VERSION 5.7 ;
  NOWIREEXTENSIONATPIN ON ;
  DIVIDERCHAR "/" ;
  BUSBITCHARS "[]" ;
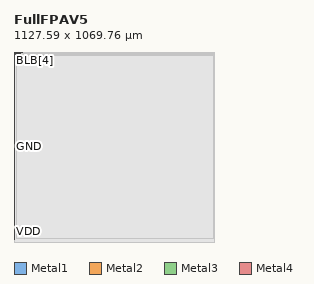
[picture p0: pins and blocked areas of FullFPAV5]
MACRO FullFPAV5
  CLASS BLOCK ;
  FOREIGN FullFPAV5 ;
  ORIGIN 4.030 43.635 ;
  SIZE 1127.585 BY 1069.755 ;
  PIN GND
    ANTENNADIFFAREA 23708.671875 ;
    PORT
      LAYER Metal1 ;
        RECT -1.255 -27.215 -0.265 1013.280 ;
    END
  END GND
  PIN VDD
    USE POWER ;
    PORT
      LAYER Metal2 ;
        RECT -1.260 -27.210 -0.270 1013.300 ;
    END
  END VDD
  PIN SF
    ANTENNAGATEAREA 1024.000000 ;
    PORT
      LAYER Metal3 ;
        RECT -3.460 1001.620 -2.905 1026.085 ;
    END
  END SF
  PIN SET
    ANTENNAGATEAREA 602.112000 ;
    PORT
      LAYER Metal3 ;
        RECT -0.725 1004.865 -0.360 1026.030 ;
    END
  END SET
  PIN IREF
    PORT
      LAYER Metal3 ;
        RECT -0.055 1010.730 0.285 1025.980 ;
    END
  END IREF
  PIN Ramp
    ANTENNADIFFAREA 559.923157 ;
    PORT
      LAYER Metal3 ;
        RECT 0.795 1011.685 1.135 1025.965 ;
    END
  END Ramp
  PIN VINP
    ANTENNADIFFAREA 1119.846313 ;
    PORT
      LAYER Metal3 ;
        RECT 29.815 1008.505 30.215 1025.625 ;
    END
  END VINP
  PIN phase
    ANTENNAGATEAREA 1324.646362 ;
    PORT
      LAYER Metal3 ;
        RECT 32.240 1003.345 32.580 1025.510 ;
    END
  END phase
  PIN RST
    ANTENNAGATEAREA 1024.000000 ;
    PORT
      LAYER Metal3 ;
        RECT 33.330 1012.435 33.670 1025.515 ;
    END
  END RST
  PIN BL[1]
    ANTENNADIFFAREA 270.950378 ;
    PORT
      LAYER Metal4 ;
        RECT 2.050 1025.745 36.770 1026.120 ;
    END
  END BL[1]
  PIN BL[0]
    ANTENNADIFFAREA 270.950378 ;
    PORT
      LAYER Metal4 ;
        RECT 1.390 1025.135 2.610 1025.455 ;
    END
  END BL[0]
  PIN BLB[1]
    ANTENNADIFFAREA 270.950378 ;
    PORT
      LAYER Metal4 ;
        RECT 3.640 1024.525 38.360 1024.845 ;
    END
  END BLB[1]
  PIN BLB[0]
    ANTENNADIFFAREA 270.950378 ;
    PORT
      LAYER Metal4 ;
        RECT 7.225 1023.785 41.945 1024.075 ;
    END
  END BLB[0]
  PIN BLB[2]
    ANTENNADIFFAREA 270.950378 ;
    PORT
      LAYER Metal4 ;
        RECT 9.315 1023.145 44.035 1023.465 ;
    END
  END BLB[2]
  PIN BLB[3]
    ANTENNADIFFAREA 270.950378 ;
    PORT
      LAYER Metal4 ;
        RECT 1.570 1022.455 12.615 1022.775 ;
    END
  END BLB[3]
  PIN BL[2]
    ANTENNADIFFAREA 270.950378 ;
    PORT
      LAYER Metal4 ;
        RECT 1.510 1021.745 13.560 1022.065 ;
    END
  END BL[2]
  PIN BLB[7]
    ANTENNADIFFAREA 270.950378 ;
    PORT
      LAYER Metal4 ;
        RECT 1.450 1017.480 25.065 1017.800 ;
    END
  END BLB[7]
  PIN BL[4]
    ANTENNADIFFAREA 270.950378 ;
    PORT
      LAYER Metal3 ;
        RECT 15.590 1019.040 15.870 1019.320 ;
      LAYER Metal4 ;
        RECT 15.590 1019.040 15.870 1019.320 ;
    END
  END BL[4]
  PIN BLB[6]
    ANTENNADIFFAREA 270.950378 ;
    PORT
      LAYER Metal3 ;
        RECT 25.725 1016.505 26.005 1016.785 ;
      LAYER Metal4 ;
        RECT 25.725 1016.505 26.005 1016.785 ;
    END
  END BLB[6]
  PIN BL[6]
    ANTENNADIFFAREA 270.950378 ;
    PORT
      LAYER Metal3 ;
        RECT 26.680 1015.420 26.960 1015.700 ;
      LAYER Metal4 ;
        RECT 26.680 1015.420 26.960 1015.700 ;
    END
  END BL[6]
  PIN BL[7]
    ANTENNADIFFAREA 270.950378 ;
    PORT
      LAYER Metal3 ;
        RECT 27.325 1014.650 27.605 1014.930 ;
      LAYER Metal4 ;
        RECT 27.325 1014.650 27.605 1014.930 ;
    END
  END BL[7]
  PIN BLB[5]
    ANTENNADIFFAREA 270.950378 ;
    PORT
      LAYER Metal4 ;
        RECT 1.440 1013.960 28.280 1014.280 ;
    END
  END BLB[5]
  PIN BLB[4]
    ANTENNADIFFAREA 270.950378 ;
    PORT
      LAYER Metal3 ;
        RECT 29.120 1013.330 29.400 1013.610 ;
      LAYER Metal4 ;
        RECT 29.120 1013.330 29.400 1013.610 ;
    END
  END BLB[4]
  PIN BL[3]
    ANTENNADIFFAREA 270.950378 ;
    PORT
      LAYER Metal3 ;
        RECT 14.190 1020.835 14.470 1021.115 ;
      LAYER Metal4 ;
        RECT 14.190 1020.835 14.470 1021.115 ;
    END
  END BL[3]
  PIN BL[5]
    ANTENNADIFFAREA 270.950378 ;
    PORT
      LAYER Metal3 ;
        RECT 14.950 1020.050 15.230 1020.330 ;
      LAYER Metal4 ;
        RECT 14.950 1020.050 15.230 1020.330 ;
    END
  END BL[5]
  OBS
      LAYER Nwell ;
        RECT 0.190 -23.210 1116.845 1010.155 ;
      LAYER Metal1 ;
        RECT 0.035 -27.215 1119.345 1013.280 ;
      LAYER Metal2 ;
        RECT 0.030 -27.215 1119.340 1013.300 ;
      LAYER Metal3 ;
        RECT -2.605 1004.565 -1.025 1026.105 ;
        RECT 1.435 1025.925 1118.670 1026.105 ;
        RECT 1.435 1011.385 29.515 1025.925 ;
        RECT 0.585 1010.430 29.515 1011.385 ;
        RECT -0.060 1008.205 29.515 1010.430 ;
        RECT 30.515 1025.815 1118.670 1025.925 ;
        RECT 30.515 1025.810 33.030 1025.815 ;
        RECT 30.515 1008.205 31.940 1025.810 ;
        RECT -0.060 1004.565 31.940 1008.205 ;
        RECT -2.605 1003.045 31.940 1004.565 ;
        RECT 32.880 1012.135 33.030 1025.810 ;
        RECT 33.970 1012.135 1118.670 1025.815 ;
        RECT 32.880 1003.045 1118.670 1012.135 ;
        RECT -2.605 1001.320 1118.670 1003.045 ;
        RECT -3.460 -43.625 1118.670 1001.320 ;
      LAYER Metal4 ;
        RECT -4.030 1025.755 1.750 1026.120 ;
        RECT -4.030 1024.835 1.090 1025.755 ;
        RECT 37.070 1025.445 1123.555 1026.120 ;
        RECT 2.910 1025.145 1123.555 1025.445 ;
        RECT 2.910 1024.835 3.340 1025.145 ;
        RECT -4.030 1024.225 3.340 1024.835 ;
        RECT 38.660 1024.375 1123.555 1025.145 ;
        RECT -4.030 1023.485 6.925 1024.225 ;
        RECT 42.245 1023.765 1123.555 1024.375 ;
        RECT -4.030 1023.075 9.015 1023.485 ;
        RECT -4.030 1022.365 1.270 1023.075 ;
        RECT 44.335 1022.845 1123.555 1023.765 ;
        RECT 12.915 1022.365 1123.555 1022.845 ;
        RECT -4.030 1021.445 1.210 1022.365 ;
        RECT 13.860 1021.445 1123.555 1022.365 ;
        RECT -4.030 1021.415 1123.555 1021.445 ;
        RECT -4.030 1020.535 13.890 1021.415 ;
        RECT 14.770 1020.630 1123.555 1021.415 ;
        RECT -4.030 1019.750 14.650 1020.535 ;
        RECT 15.530 1019.750 1123.555 1020.630 ;
        RECT -4.030 1019.620 1123.555 1019.750 ;
        RECT -4.030 1018.740 15.290 1019.620 ;
        RECT 16.170 1018.740 1123.555 1019.620 ;
        RECT -4.030 1018.100 1123.555 1018.740 ;
        RECT -4.030 1017.180 1.150 1018.100 ;
        RECT 25.365 1017.180 1123.555 1018.100 ;
        RECT -4.030 1017.085 1123.555 1017.180 ;
        RECT -4.030 1016.205 25.425 1017.085 ;
        RECT 26.305 1016.205 1123.555 1017.085 ;
        RECT -4.030 1016.000 1123.555 1016.205 ;
        RECT -4.030 1015.120 26.380 1016.000 ;
        RECT 27.260 1015.230 1123.555 1016.000 ;
        RECT -4.030 1014.580 27.025 1015.120 ;
        RECT 27.905 1014.580 1123.555 1015.230 ;
        RECT -4.030 1013.660 1.140 1014.580 ;
        RECT 28.580 1013.910 1123.555 1014.580 ;
        RECT 28.580 1013.660 28.820 1013.910 ;
        RECT -4.030 1013.030 28.820 1013.660 ;
        RECT 29.700 1013.030 1123.555 1013.910 ;
        RECT -4.030 -43.635 1123.555 1013.030 ;
      LAYER Metal5 ;
        RECT 7.800 -25.000 1118.260 1007.190 ;
  END
END FullFPAV5
END LIBRARY

